VERSION 5.7 ;
  NOWIREEXTENSIONATPIN ON ;
  DIVIDERCHAR "/" ;
  BUSBITCHARS "[]" ;
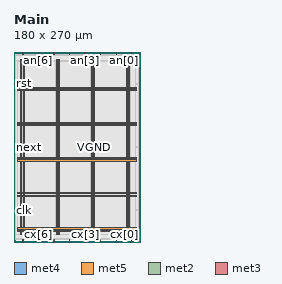
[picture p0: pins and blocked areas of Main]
MACRO Main
  CLASS BLOCK ;
  FOREIGN Main ;
  ORIGIN 0.000 0.000 ;
  SIZE 180.000 BY 270.000 ;
  PIN VGND
    DIRECTION INOUT ;
    USE GROUND ;
    PORT
      LAYER met4 ;
        RECT 13.020 10.640 14.620 258.640 ;
    END
    PORT
      LAYER met4 ;
        RECT 63.020 10.640 64.620 258.640 ;
    END
    PORT
      LAYER met4 ;
        RECT 113.020 10.640 114.620 258.640 ;
    END
    PORT
      LAYER met4 ;
        RECT 163.020 10.640 164.620 258.640 ;
    END
    PORT
      LAYER met5 ;
        RECT 5.280 18.380 174.580 19.980 ;
    END
    PORT
      LAYER met5 ;
        RECT 5.280 68.380 174.580 69.980 ;
    END
    PORT
      LAYER met5 ;
        RECT 5.280 118.380 174.580 119.980 ;
    END
    PORT
      LAYER met5 ;
        RECT 5.280 168.380 174.580 169.980 ;
    END
    PORT
      LAYER met5 ;
        RECT 5.280 218.380 174.580 219.980 ;
    END
  END VGND
  PIN VPWR
    DIRECTION INOUT ;
    USE POWER ;
    PORT
      LAYER met4 ;
        RECT 9.720 10.640 11.320 258.640 ;
    END
    PORT
      LAYER met4 ;
        RECT 59.720 10.640 61.320 258.640 ;
    END
    PORT
      LAYER met4 ;
        RECT 109.720 10.640 111.320 258.640 ;
    END
    PORT
      LAYER met4 ;
        RECT 159.720 10.640 161.320 258.640 ;
    END
    PORT
      LAYER met5 ;
        RECT 5.280 15.080 174.580 16.680 ;
    END
    PORT
      LAYER met5 ;
        RECT 5.280 65.080 174.580 66.680 ;
    END
    PORT
      LAYER met5 ;
        RECT 5.280 115.080 174.580 116.680 ;
    END
    PORT
      LAYER met5 ;
        RECT 5.280 165.080 174.580 166.680 ;
    END
    PORT
      LAYER met5 ;
        RECT 5.280 215.080 174.580 216.680 ;
    END
  END VPWR
  PIN an[0]
    DIRECTION OUTPUT ;
    USE SIGNAL ;
    ANTENNADIFFAREA 0.340600 ;
    PORT
      LAYER met2 ;
        RECT 167.070 266.000 167.350 270.000 ;
    END
  END an[0]
  PIN an[1]
    DIRECTION OUTPUT ;
    USE SIGNAL ;
    ANTENNADIFFAREA 0.340600 ;
    PORT
      LAYER met2 ;
        RECT 144.990 266.000 145.270 270.000 ;
    END
  END an[1]
  PIN an[2]
    DIRECTION OUTPUT ;
    USE SIGNAL ;
    ANTENNADIFFAREA 0.340600 ;
    PORT
      LAYER met2 ;
        RECT 122.910 266.000 123.190 270.000 ;
    END
  END an[2]
  PIN an[3]
    DIRECTION OUTPUT ;
    USE SIGNAL ;
    ANTENNADIFFAREA 0.340600 ;
    PORT
      LAYER met2 ;
        RECT 100.830 266.000 101.110 270.000 ;
    END
  END an[3]
  PIN an[4]
    DIRECTION OUTPUT ;
    USE SIGNAL ;
    ANTENNADIFFAREA 0.340600 ;
    PORT
      LAYER met2 ;
        RECT 78.750 266.000 79.030 270.000 ;
    END
  END an[4]
  PIN an[5]
    DIRECTION OUTPUT ;
    USE SIGNAL ;
    ANTENNADIFFAREA 0.340600 ;
    PORT
      LAYER met2 ;
        RECT 56.670 266.000 56.950 270.000 ;
    END
  END an[5]
  PIN an[6]
    DIRECTION OUTPUT ;
    USE SIGNAL ;
    ANTENNADIFFAREA 0.340600 ;
    PORT
      LAYER met2 ;
        RECT 34.590 266.000 34.870 270.000 ;
    END
  END an[6]
  PIN an[7]
    DIRECTION OUTPUT ;
    USE SIGNAL ;
    ANTENNADIFFAREA 0.340600 ;
    PORT
      LAYER met2 ;
        RECT 12.510 266.000 12.790 270.000 ;
    END
  END an[7]
  PIN clk
    DIRECTION INPUT ;
    USE SIGNAL ;
    ANTENNAGATEAREA 0.852000 ;
    PORT
      LAYER met3 ;
        RECT 0.000 44.920 4.000 45.520 ;
    END
  END clk
  PIN cx[0]
    DIRECTION OUTPUT ;
    USE SIGNAL ;
    PORT
      LAYER met2 ;
        RECT 167.070 0.000 167.350 4.000 ;
    END
  END cx[0]
  PIN cx[1]
    DIRECTION OUTPUT ;
    USE SIGNAL ;
    ANTENNADIFFAREA 0.340600 ;
    PORT
      LAYER met2 ;
        RECT 144.990 0.000 145.270 4.000 ;
    END
  END cx[1]
  PIN cx[2]
    DIRECTION OUTPUT ;
    USE SIGNAL ;
    ANTENNADIFFAREA 0.340600 ;
    PORT
      LAYER met2 ;
        RECT 122.910 0.000 123.190 4.000 ;
    END
  END cx[2]
  PIN cx[3]
    DIRECTION OUTPUT ;
    USE SIGNAL ;
    ANTENNADIFFAREA 0.340600 ;
    PORT
      LAYER met2 ;
        RECT 100.830 0.000 101.110 4.000 ;
    END
  END cx[3]
  PIN cx[4]
    DIRECTION OUTPUT ;
    USE SIGNAL ;
    ANTENNADIFFAREA 0.340600 ;
    PORT
      LAYER met2 ;
        RECT 78.750 0.000 79.030 4.000 ;
    END
  END cx[4]
  PIN cx[5]
    DIRECTION OUTPUT ;
    USE SIGNAL ;
    ANTENNADIFFAREA 0.340600 ;
    PORT
      LAYER met2 ;
        RECT 56.670 0.000 56.950 4.000 ;
    END
  END cx[5]
  PIN cx[6]
    DIRECTION OUTPUT ;
    USE SIGNAL ;
    ANTENNADIFFAREA 0.340600 ;
    PORT
      LAYER met2 ;
        RECT 34.590 0.000 34.870 4.000 ;
    END
  END cx[6]
  PIN cx[7]
    DIRECTION OUTPUT ;
    USE SIGNAL ;
    ANTENNADIFFAREA 0.340600 ;
    PORT
      LAYER met2 ;
        RECT 12.510 0.000 12.790 4.000 ;
    END
  END cx[7]
  PIN next
    DIRECTION INPUT ;
    USE SIGNAL ;
    ANTENNAGATEAREA 0.126000 ;
    PORT
      LAYER met3 ;
        RECT 0.000 134.680 4.000 135.280 ;
    END
  END next
  PIN rst
    DIRECTION INPUT ;
    USE SIGNAL ;
    ANTENNAGATEAREA 0.213000 ;
    PORT
      LAYER met3 ;
        RECT 0.000 224.440 4.000 225.040 ;
    END
  END rst
  OBS
      LAYER nwell ;
        RECT 5.330 10.795 174.530 258.590 ;
      LAYER li1 ;
        RECT 5.520 10.795 174.340 258.485 ;
      LAYER met1 ;
        RECT 1.910 10.240 176.570 261.420 ;
      LAYER met2 ;
        RECT 1.930 265.720 12.230 266.000 ;
        RECT 13.070 265.720 34.310 266.000 ;
        RECT 35.150 265.720 56.390 266.000 ;
        RECT 57.230 265.720 78.470 266.000 ;
        RECT 79.310 265.720 100.550 266.000 ;
        RECT 101.390 265.720 122.630 266.000 ;
        RECT 123.470 265.720 144.710 266.000 ;
        RECT 145.550 265.720 166.790 266.000 ;
        RECT 167.630 265.720 176.550 266.000 ;
        RECT 1.930 4.280 176.550 265.720 ;
        RECT 1.930 4.000 12.230 4.280 ;
        RECT 13.070 4.000 34.310 4.280 ;
        RECT 35.150 4.000 56.390 4.280 ;
        RECT 57.230 4.000 78.470 4.280 ;
        RECT 79.310 4.000 100.550 4.280 ;
        RECT 101.390 4.000 122.630 4.280 ;
        RECT 123.470 4.000 144.710 4.280 ;
        RECT 145.550 4.000 166.790 4.280 ;
        RECT 167.630 4.000 176.550 4.280 ;
      LAYER met3 ;
        RECT 1.905 225.440 176.575 258.565 ;
        RECT 4.400 224.040 176.575 225.440 ;
        RECT 1.905 135.680 176.575 224.040 ;
        RECT 4.400 134.280 176.575 135.680 ;
        RECT 1.905 45.920 176.575 134.280 ;
        RECT 4.400 44.520 176.575 45.920 ;
        RECT 1.905 10.715 176.575 44.520 ;
      LAYER met4 ;
        RECT 4.895 21.255 9.320 256.865 ;
        RECT 11.720 21.255 12.620 256.865 ;
        RECT 15.020 21.255 59.320 256.865 ;
        RECT 61.720 21.255 62.620 256.865 ;
        RECT 65.020 21.255 109.320 256.865 ;
        RECT 111.720 21.255 112.620 256.865 ;
        RECT 115.020 21.255 159.320 256.865 ;
        RECT 161.720 21.255 162.620 256.865 ;
        RECT 165.020 21.255 172.665 256.865 ;
  END
END Main
END LIBRARY

